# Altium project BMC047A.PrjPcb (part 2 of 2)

## Sheet BMC047A USB.SchDoc
size 431 x 279 mm; Date: Not shown in title block; ApprovedBy: Not shown in title block; CheckedBy: Not shown in title block; Author: Not shown in title block; CompanyName: Not shown in title block; Engineer: Not shown in title block; Organization: Not shown in title block; Address1: Not shown in title block; Address2: Not shown in title block; Address3: Not shown in title block; Address4: Not shown in title block; DocumentNumber: 2; Revision: Use project parameter SCH_Rev; SheetNumber: 2; SheetTotal: 3; PageSetup: Record=PageOptions¦CenterHorizontal=True¦CenterVertical=True¦PrintScale=0.96¦XCorrection=1.00¦YCorrection=1.00¦PrintKind=0¦BorderSize=5000000¦LeftOffset=0¦BottomOffset=0¦Orientation=2¦PaperLength=1000¦PaperWidth=1000¦Scale=100¦PaperSource=15¦PrintQuality=-3¦MediaType=1¦DitherType=10¦PrintScaleMode=1¦PaperKind=Tabloid (11 x 17")¦PaperIndex=17

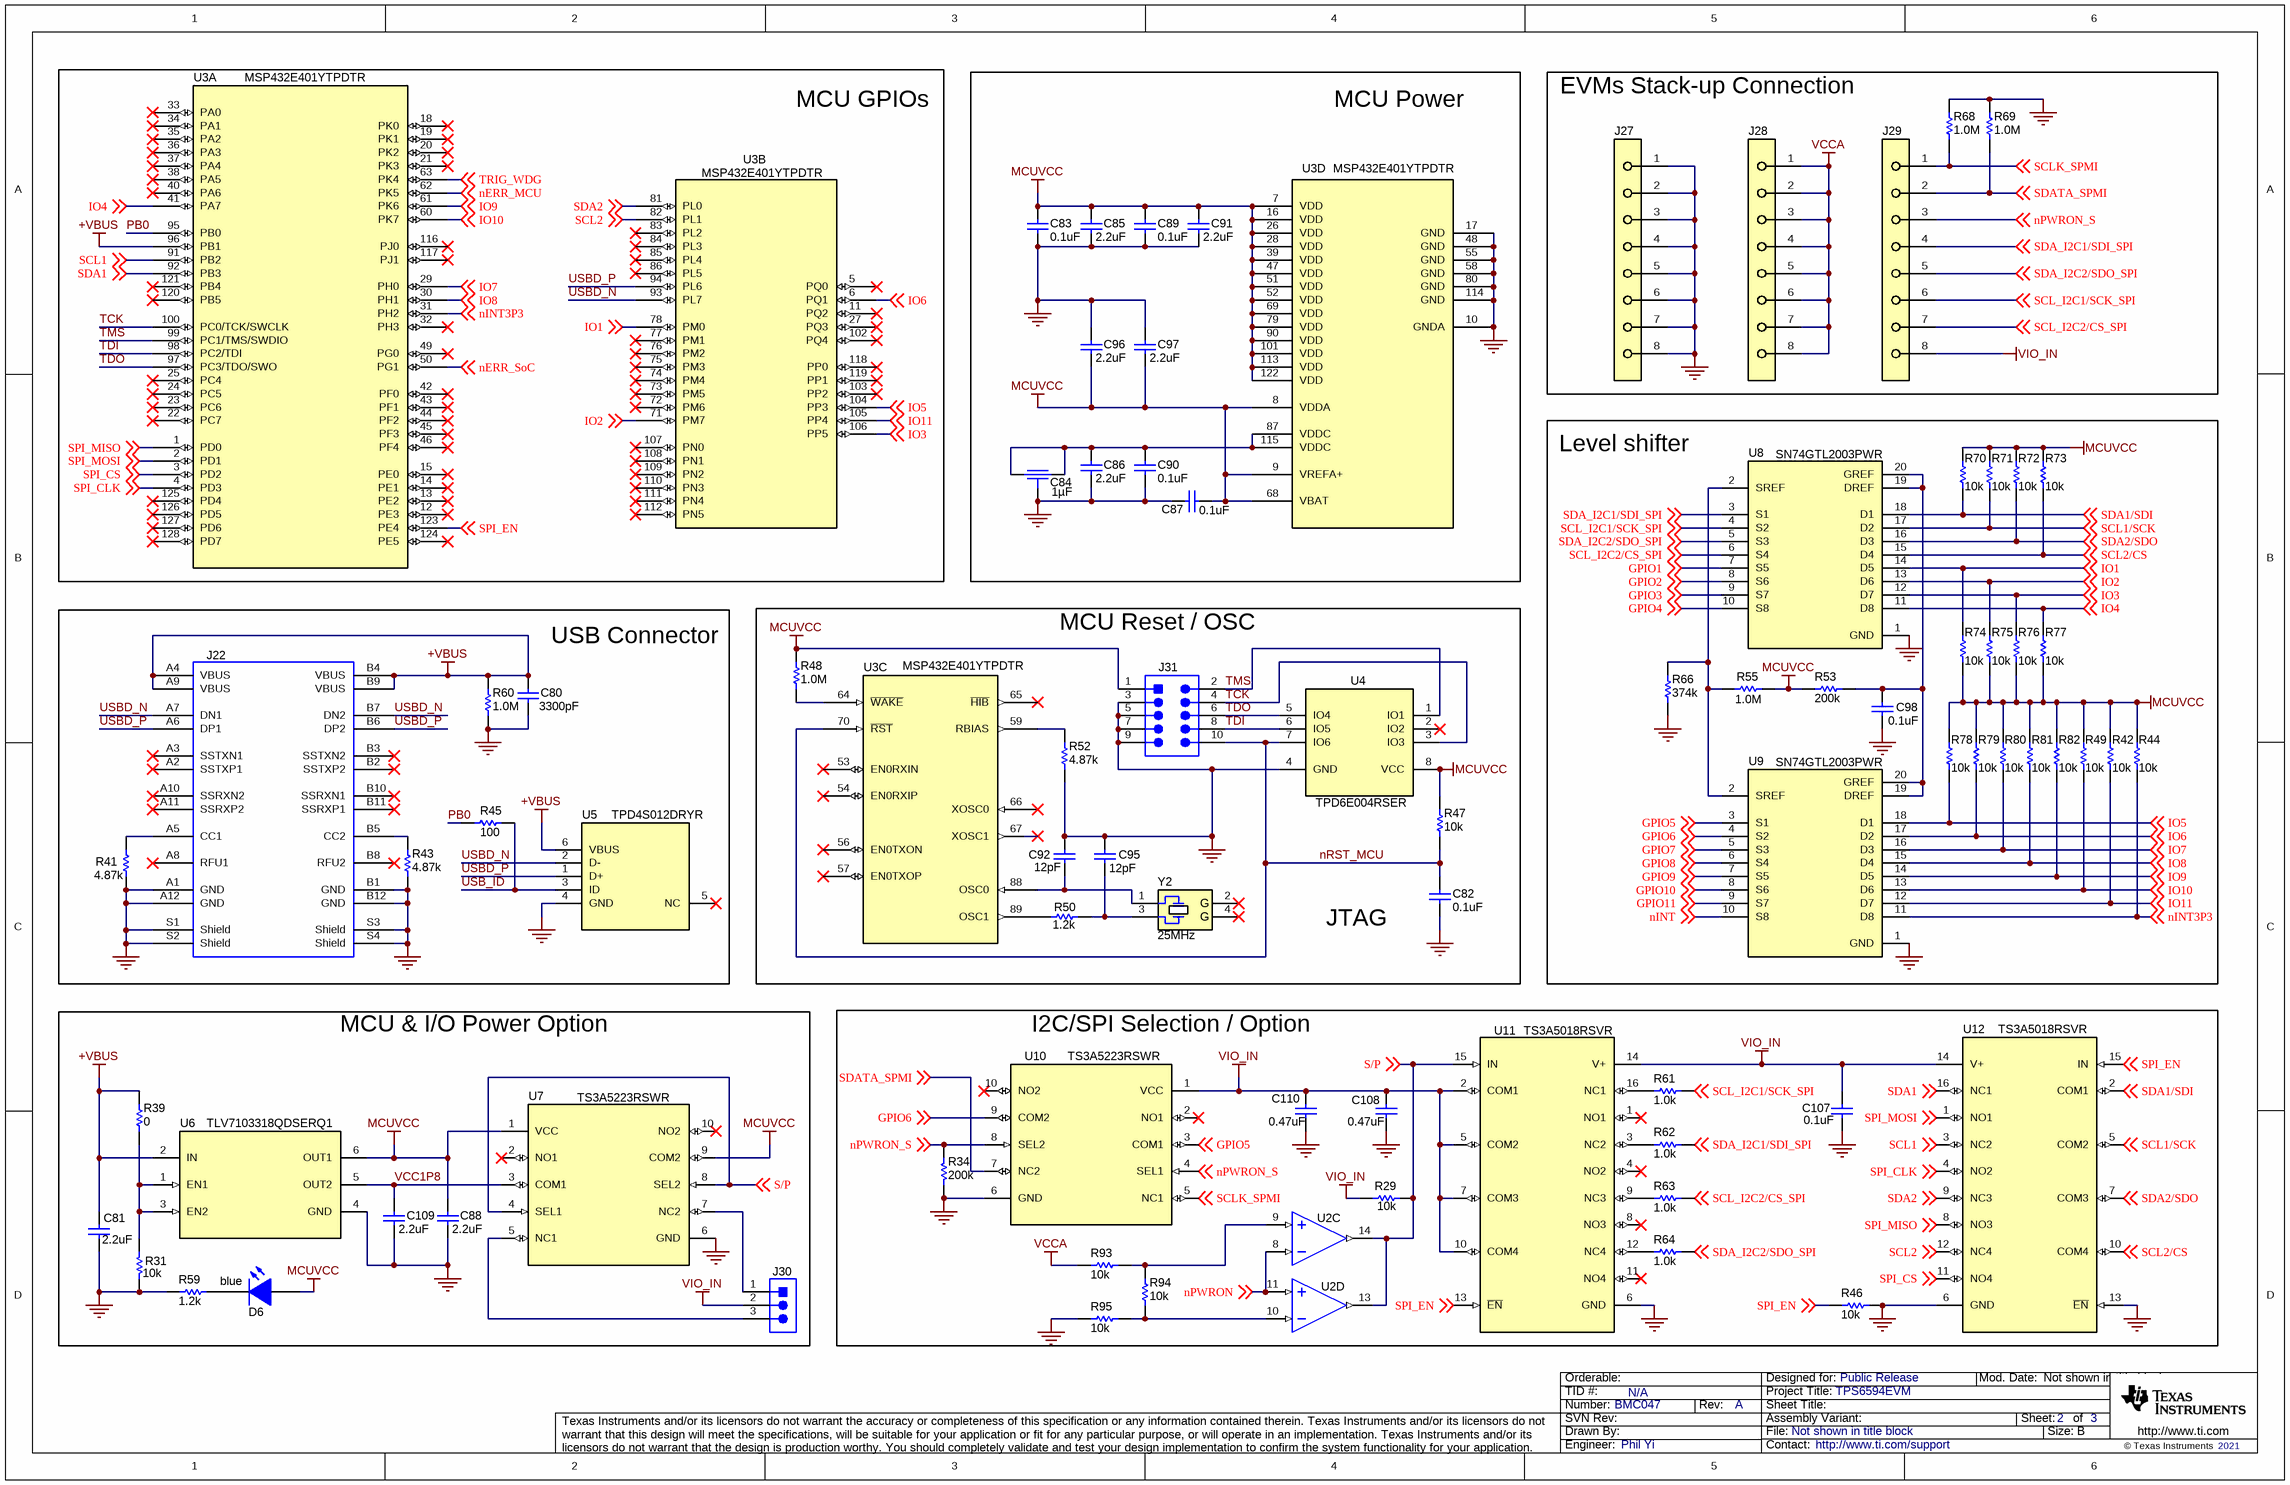
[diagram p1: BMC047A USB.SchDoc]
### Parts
C80  ValueDisplayed: 3300pF  [0603L]  (hidden comment: C0603C332K5RACTU)
C81  ValueDisplayed: 2.2uF  [0603L]  (hidden comment: CGA3E1X7S1C225M080AC)
C82  ValueDisplayed: 0.1uF  [0402L]  (hidden comment: GCM155R71C104KA55D)
C83  ValueDisplayed: 0.1uF  [0402L]  (hidden comment: GCM155R71C104KA55D)
C84  ValueDisplayed: 1µF  [FP-NFM15HC105D0G3_0402-MFG]  (hidden comment: NFM15HC105D0G3)
C85  ValueDisplayed: 2.2uF  [0603L]  (hidden comment: CGA3E1X7S1C225M080AC)
C86  ValueDisplayed: 2.2uF  [0603L]  (hidden comment: CGA3E1X7S1C225M080AC)
C87  ValueDisplayed: 0.1uF  [0402L]  (hidden comment: GCM155R71C104KA55D)
C88  ValueDisplayed: 2.2uF  [0603L]  (hidden comment: CGA3E1X7S1C225M080AC)
C89  ValueDisplayed: 0.1uF  [0402L]  (hidden comment: GCM155R71C104KA55D)
C90  ValueDisplayed: 0.1uF  [0402L]  (hidden comment: GCM155R71C104KA55D)
C91  ValueDisplayed: 2.2uF  [0603L]  (hidden comment: CGA3E1X7S1C225M080AC)
C92  ValueDisplayed: 12pF  [0402L]  (hidden comment: GCM1555C1H120JA16J)
C95  ValueDisplayed: 12pF  [0402L]  (hidden comment: GCM1555C1H120JA16J)
C96  ValueDisplayed: 2.2uF  [0603L]  (hidden comment: CGA3E1X7S1C225M080AC)
C97  ValueDisplayed: 2.2uF  [0603L]  (hidden comment: CGA3E1X7S1C225M080AC)
C98  value 0.1uF  [0402L]  (hidden comment: GCM155R71C104KA55D)
C107  ValueDisplayed: 0.1uF  [0402L]  (hidden comment: GCM155R71C104KA55D)
C108  ValueDisplayed: 0.47uF  [0402L]  (hidden comment: GCM155C71A474KE36D)
C109  ValueDisplayed: 2.2uF  [0603L]  (hidden comment: CGA3E1X7S1C225M080AC)
C110  ValueDisplayed: 0.47uF  [0402L]  (hidden comment: GCM155C71A474KE36D)
D6  Color: blue  [LB Q39G_BLUE]  (hidden comment: LB Q39G-L2N2-35-1)
J22  12401610E4#2A  [Amphenol_12401610E4_2A]  (value not drawn)
J27  ESQ-108-14-T-S  [FP-ESQ-108-14-T-S_HDR8-MFG]  (value not drawn)
J28  ESQ-108-14-T-S  [FP-ESQ-108-14-T-S_HDR8-MFG]  (value not drawn)
J29  ESQ-108-14-T-S  [FP-ESQ-108-14-T-S_HDR8-MFG]  (value not drawn)
J30  61300311121  [WURTH_61300311121]  (value not drawn)
J31  SH-105-01-F-DV-K  [Samtec_FTSH-105-01-x-DV-K]  (value not drawn)
R29  ValueDisplayed: 10k  [0402L]  (hidden comment: CRCW040210K0JNED)
R31  ValueDisplayed: 10k  [0402L]  (hidden comment: CRCW040210K0JNED)
R34  ValueDisplayed: 200k  [0402]  (hidden comment: CRCW0402200KJNED)
R39  ValueDisplayed: 0  [0402L]  (hidden comment: RK73Z1ETTP)
R41  ValueDisplayed: 4.87k  [0402L]  (hidden comment: CRCW04024K87FKED)
R42  ValueDisplayed: 10k  [0402L]  (hidden comment: CRCW040210K0JNED)
R43  ValueDisplayed: 4.87k  [0402L]  (hidden comment: CRCW04024K87FKED)
R44  ValueDisplayed: 10k  [0402L]  (hidden comment: CRCW040210K0JNED)
R45  ValueDisplayed: 100  [0402L]  (hidden comment: CRCW0402100RJNED)
R46  ValueDisplayed: 10k  [0402L]  (hidden comment: CRCW040210K0JNED)
R47  ValueDisplayed: 10k  [0402L]  (hidden comment: CRCW040210K0JNED)
R48  ValueDisplayed: 1.0M  [0402L]  (hidden comment: CRCW04021M00JNED)
R49  ValueDisplayed: 10k  [0402L]  (hidden comment: CRCW040210K0JNED)
R50  ValueDisplayed: 1.2k  [0402L]  (hidden comment: CRCW04021K20JNED)
R52  ValueDisplayed: 4.87k  [0402L]  (hidden comment: CRCW04024K87FKED)
R53  ValueDisplayed: 200k  [0402]  (hidden comment: CRCW0402200KJNED)
R55  ValueDisplayed: 1.0M  [0402L]  (hidden comment: CRCW04021M00JNED)
R59  ValueDisplayed: 1.2k  [0402L]  (hidden comment: CRCW04021K20JNED)
R60  ValueDisplayed: 1.0M  [0402L]  (hidden comment: CRCW04021M00JNED)
R61  value 1.0k  [0402L]  (hidden comment: CRCW04021K00JNED)
R62  value 1.0k  [0402L]  (hidden comment: CRCW04021K00JNED)
R63  value 1.0k  [0402L]  (hidden comment: CRCW04021K00JNED)
R64  value 1.0k  [0402L]  (hidden comment: CRCW04021K00JNED)
R66  ValueDisplayed: 374k  [0402L]  (hidden comment: CRCW0402374KFKED)
R68  ValueDisplayed: 1.0M  [0402L]  (hidden comment: CRCW04021M00JNED)
R69  ValueDisplayed: 1.0M  [0402L]  (hidden comment: CRCW04021M00JNED)
R70  ValueDisplayed: 10k  [0402L]  (hidden comment: CRCW040210K0JNED)
R71  ValueDisplayed: 10k  [0402L]  (hidden comment: CRCW040210K0JNED)
R72  ValueDisplayed: 10k  [0402L]  (hidden comment: CRCW040210K0JNED)
R73  ValueDisplayed: 10k  [0402L]  (hidden comment: CRCW040210K0JNED)
R74  ValueDisplayed: 10k  [0402L]  (hidden comment: CRCW040210K0JNED)
R75  ValueDisplayed: 10k  [0402L]  (hidden comment: CRCW040210K0JNED)
R76  ValueDisplayed: 10k  [0402L]  (hidden comment: CRCW040210K0JNED)
R77  ValueDisplayed: 10k  [0402L]  (hidden comment: CRCW040210K0JNED)
R78  ValueDisplayed: 10k  [0402L]  (hidden comment: CRCW040210K0JNED)
R79  ValueDisplayed: 10k  [0402L]  (hidden comment: CRCW040210K0JNED)
R80  ValueDisplayed: 10k  [0402L]  (hidden comment: CRCW040210K0JNED)
R81  ValueDisplayed: 10k  [0402L]  (hidden comment: CRCW040210K0JNED)
R82  ValueDisplayed: 10k  [0402L]  (hidden comment: CRCW040210K0JNED)
R93  ValueDisplayed: 10k  [0402L]  (hidden comment: CRCW040210K0JNED)
R94  ValueDisplayed: 10k  [0402L]  (hidden comment: CRCW040210K0JNED)
R95  ValueDisplayed: 10k  [0402L]  (hidden comment: CRCW040210K0JNED)
U2  LM2901AVQPWRQ1  [PW0014A_N]  (value not drawn)  (parts C,D of 5)
U3  MSP432E401YTPDTR  [PDT0128A]  (parts A,B,C,D of 4)
U4  TPD6E004RSER  [RSE0008A]
U5  TPD4S012DRYR  [DRY0006A]
U6  TLV7103318QDSERQ1  [DSE0006A]
U7  TS3A5223RSWR  [RSW0010A]
U8  SN74GTL2003PWR  [PW0020A_N]
U9  SN74GTL2003PWR  [PW0020A_N]
U10  TS3A5223RSWR  [RSW0010A]
U11  TS3A5018RSVR  [RSV0016A]
U12  TS3A5018RSVR  [RSV0016A]
Y2  Frequency_Fixed: 25MHz  [NDK_NX3225GA]  (hidden comment: NX3225GA-25.000M-STD-CRG-2)

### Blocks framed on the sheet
MCU GPIOs: U3
MCU Power: C83-C87 C89-C91 C96 C97 U3
EVMs Stack-up Connection: J27-J29 R68 R69
Level shifter: C98 R42 R44 R49 R53 R55 R66 R70-R82 U8 U9
USB Connector: C80 J22 R41 R43 R45 R60 U5
MCU & I/O Power Option: C81 C88 C109 D6 J30 R31 R39 R59 U6 U7
I2C/SPI Selection / Option: C107 C108 C110 R29 R34 R46 R61-R64 R93-R95 U2 U10-U12

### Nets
+VBUS: C80.1 C81.1 J22.A4(VBUS) J22.A9(VBUS) J22.B4(VBUS) J22.B9(VBUS) R39.1 R60.1 U3.96(PB1) U5.6(VBUS) U6.2(IN)
GND: C80.2 C81.2 C82.2 C83.2 C84.2 C85.2 C86.2 C87.1 C88.2 C89.2 C90.2 C91.2 C92.2 C95.2 C96.1 C97.1 C98.2 C107.1 C108.1 C109.2 C110.1 J22.A1(GND) J22.A12(GND) J22.B1(GND) J22.B12(GND) J22.S1(Shield) J22.S2(Shield) J22.S3(Shield) J22.S4(Shield) J27.1 J27.2 J27.3 J27.4 J27.5 J27.6 J27.7 J27.8 J31.3 J31.5 J31.7 J31.9 R31.1 R34.1 R41.2 R43.2 R46.1 R52.2 R59.2 R60.2 R66.1 R68.1 R69.1 R95.2 U3.10(GNDA) U3.17(GND) U3.48(GND) U3.55(GND) U3.58(GND) U3.80(GND) U3.114(GND) U4.4(GND) U5.4(GND) U6.4(GND) U7.6(GND) U8.1(GND) U9.1(GND) U10.6(GND) U11.6(GND) U12.6(GND) U12.13(~{EN})
MCUVCC: C83.1 C85.1 C87.2 C88.1 C89.1 C91.1 C96.2 C97.2 D6.1(A) J31.1 R42.1 R44.1 R47.2 R48.2 R49.1 R53.1 R55.2 R70.1 R71.1 R72.1 R73.1 R74.2 R75.2 R76.2 R77.2 R78.1 R79.1 R80.1 R81.1 R82.1 U3.7(VDD) U3.8(VDDA) U3.9(VREFA+) U3.16(VDD) U3.26(VDD) U3.28(VDD) U3.39(VDD) U3.47(VDD) U3.51(VDD) U3.52(VDD) U3.68(VBAT) U3.69(VDD) U3.79(VDD) U3.90(VDD) U3.101(VDD) U3.113(VDD) U3.122(VDD) U4.8(VCC) U6.6(OUT1) U7.1(VCC) U7.9(COM2)
VCCA: J28.1 J28.2 J28.3 J28.4 J28.5 J28.6 J28.7 J28.8 R93.1
VIO_IN: C107.2 C108.2 C110.2 J29.8 J30.2 R29.1 U10.1(VCC) U11.2(COM1) U11.5(COM2) U11.7(COM3) U11.10(COM4) U11.14(V+) U12.14(V+)
GPIO1: U8.7(S5) ; off-sheet GPIO1
GPIO2: U8.8(S6) ; off-sheet GPIO2
GPIO3: U8.9(S7) ; off-sheet GPIO3
GPIO4: U8.10(S8) ; off-sheet GPIO4
GPIO5: U9.3(S1) U10.3(COM1) ; off-sheet GPIO5
GPIO6: U9.4(S2) U10.9(COM2) ; off-sheet GPIO6
GPIO7: U9.5(S3) ; off-sheet GPIO7
GPIO8: U9.6(S4) ; off-sheet GPIO8
GPIO9: U9.7(S5) ; off-sheet GPIO9
GPIO10: U9.8(S6) ; off-sheet GPIO10
GPIO11: U9.9(S7) ; off-sheet GPIO11
IO1: R74.1 U3.78(PM0) U8.14(D5) ; off-sheet IO1
IO2: R75.1 U3.71(PM7) U8.13(D6) ; off-sheet IO2
IO3: R76.1 U3.106(PP5) U8.12(D7) ; off-sheet IO3
IO4: R77.1 U3.41(PA7) U8.11(D8) ; off-sheet IO4
IO5: R78.2 U3.104(PP3) U9.18(D1) ; off-sheet IO5
IO6: R79.2 U3.6(PQ1) U9.17(D2) ; off-sheet IO6
IO7: R80.2 U3.29(PH0) U9.16(D3) ; off-sheet IO7
IO8: R81.2 U3.30(PH1) U9.15(D4) ; off-sheet IO8
IO9: R82.2 U3.61(PK6) U9.14(D5) ; off-sheet IO9
IO10: R49.2 U3.60(PK7) U9.13(D6) ; off-sheet IO10
IO11: R42.2 U3.105(PP4) U9.12(D7) ; off-sheet IO11
nERR_MCU: U3.62(PK5) ; off-sheet nERR_MCU
nERR_SoC: U3.50(PG1) ; off-sheet nERR_SoC
nINT: U9.10(S8) ; off-sheet nINT
nINT3P3: R44.2 U3.31(PH2) U9.11(D8) ; off-sheet nINT3P3
nPWRON: U2.8(-IN3) U2.11(+IN4) ; off-sheet nPWRON
nPWRON_S: J29.3 R34.2 U10.4(SEL1) U10.8(SEL2) ; off-sheet nPWRON_S
nRST_MCU: C82.1 J31.10 R47.1 U3.70(~{RST}) U4.7(IO6)
PB0: R45.1 U3.95(PB0)
S/P: R29.2 U2.13(OUT4) U2.14(OUT3) U7.4(SEL1) U7.8(SEL2) U11.15(IN) ; off-sheet S/P
SCL1: U3.91(PB2) U12.3(NC2) ; off-sheet SCL1
SCL1/SCK: R71.2 U8.17(D2) U12.5(COM2) ; off-sheet SCL1/SCK
SCL2: U3.82(PL1) U12.12(NC4) ; off-sheet SCL2
SCL2/CS: R73.2 U8.15(D4) U12.10(COM4) ; off-sheet SCL2/CS
SCL_I2C1/SCK_SPI: J29.6 R61.2 U8.4(S2) ; off-sheet SCL_I2C1/SCK_SPI
SCL_I2C2/CS_SPI: J29.7 R63.2 U8.6(S4) ; off-sheet SCL_I2C2/CS_SPI
SCLK_SPMI: J29.1 R68.2 U10.5(NC1) ; off-sheet SCLK_SPMI
SDA1: U3.92(PB3) U12.16(NC1) ; off-sheet SDA1
SDA1/SDI: R70.2 U8.18(D1) U12.2(COM1) ; off-sheet SDA1/SDI
SDA2: U3.81(PL0) U12.9(NC3) ; off-sheet SDA2
SDA2/SDO: R72.2 U8.16(D3) U12.7(COM3) ; off-sheet SDA2/SDO
SDA_I2C1/SDI_SPI: J29.4 R62.2 U8.3(S1) ; off-sheet SDA_I2C1/SDI_SPI
SDA_I2C2/SDO_SPI: J29.5 R64.2 U8.5(S3) ; off-sheet SDA_I2C2/SDO_SPI
SDATA_SPMI: J29.2 R69.2 U10.7(NC2) ; off-sheet SDATA_SPMI
SPI_CLK: U3.4(PD3) U12.4(NO2) ; off-sheet SPI_CLK
SPI_CS: U3.3(PD2) U12.11(NO4) ; off-sheet SPI_CS
SPI_EN: R46.2 U3.123(PE4) U11.13(~{EN}) U12.15(IN) ; off-sheet SPI_EN
SPI_MISO: U3.1(PD0) U12.8(NO3) ; off-sheet SPI_MISO
SPI_MOSI: U3.2(PD1) U12.1(NO1) ; off-sheet SPI_MOSI
TCK: J31.4 U3.100(PC0/TCK/SWCLK) U4.3(IO3)
TDI: J31.8 U3.98(PC2/TDI) U4.6(IO5)
TDO: J31.6 U3.97(PC3/TDO/SWO) U4.5(IO4)
TMS: J31.2 U3.99(PC1/TMS/SWDIO) U4.1(IO1)
TRIG_WDG: U3.63(PK4) ; off-sheet TRIG_WDG
USB_ID: R45.2 U5.3(ID)
USBD_N: J22.A7(DN1) J22.B7(DN2) U3.93(PL7) U5.2(D-)
USBD_P: J22.A6(DP1) J22.B6(DP2) U3.94(PL6) U5.1(D+)
VCC1P8: C109.1 U6.5(OUT2) U7.3(COM1)
NetC84_1: C84.1 C84.3 C86.1 C90.1 U3.87(VDDC) U3.115(VDDC)
NetC92_1: C92.1 U3.88(OSC0) Y2.1
NetC95_1: C95.1 R50.2 Y2.3
NetC98_1: C98.1 R53.2 U8.19(DREF) U8.20(GREF) U9.19(DREF) U9.20(GREF)
NetD6_2: D6.2(K) R59.1
NetJ22_A5: J22.A5(CC1) R41.1
NetJ22_B5: J22.B5(CC2) R43.1
NetJ30_1: J30.1 U7.7(NC2)
NetJ30_3: J30.3 U7.5(NC1)
NetR31_2: R31.2 R39.2 U6.1(EN1) U6.3(EN2)
NetR48_1: R48.1 U3.64(~{WAKE})
NetR50_1: R50.1 U3.89(OSC1)
NetR52_1: R52.1 U3.59(RBIAS)
NetR55_1: R55.1 R66.2 U8.2(SREF) U9.2(SREF)
NetR61_1: R61.1 U11.16(NC1)
NetR62_1: R62.1 U11.3(NC2)
NetR63_1: R63.1 U11.9(NC3)
NetR64_1: R64.1 U11.12(NC4)
NetR93_2: R93.2 R94.2 U2.9(+IN3)
NetR94_1: R94.1 R95.1 U2.10(-IN4)

Not connected (* = marked no-connect by the designer): J22 A2(SSTXP1)* A3(SSTXN1)* A8(RFU1)* A10(SSRXN2)* A11(SSRXP2)* B2(SSTXP2)* B3(SSTXN2)* B8(RFU2)* B10(SSRXN1)* B11(SSRXP1)*; U3 5(PQ0)* 11(PQ2)* 12(PE3)* 13(PE2)* 14(PE1)* 15(PE0)* 18(PK0)* 19(PK1)* 20(PK2)* 21(PK3)* 22(PC7)* 23(PC6)* 24(PC5)* 25(PC4)* 27(PQ3)* 32(PH3)* 33(PA0)* 34(PA1)* 35(PA2)* 36(PA3)* 37(PA4)* 38(PA5)* 40(PA6)* 42(PF0)* 43(PF1)* 44(PF2)* 45(PF3)* 46(PF4)* 49(PG0)* 53(EN0RXIN)* 54(EN0RXIP)* 56(EN0TXON)* 57(EN0TXOP)* 65(~{HIB})* 66(XOSC0)* 67(XOSC1)* 72(PM6)* 73(PM5)* 74(PM4)* 75(PM3)* 76(PM2)* 77(PM1)* 83(PL2)* 84(PL3)* 85(PL4)* 86(PL5)* 102(PQ4)* 103(PP2)* 107(PN0)* 108(PN1)* 109(PN2)* 110(PN3)* 111(PN4)* 112(PN5)* 116(PJ0)* 117(PJ1)* 118(PP0)* 119(PP1)* 120(PB5)* 121(PB4)* 124(PE5)* 125(PD4)* 126(PD5)* 127(PD6)* 128(PD7)*; U4 2(IO2)*; U5 5(NC)*; U7 2(NO1)* 10(NO2)*; U10 2(NO1)* 10(NO2)*; U11 1(NO1)* 4(NO2)* 8(NO3)* 11(NO4)*; Y2 2(GND)* 4(GND)*

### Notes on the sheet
- MCU Reset / OSC
- JTAG

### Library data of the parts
C80 = CMP-0006922-4: CAP, CERM, 3300 pF, 50 V, +/- 10%, X7R, 0603; Manufacturer: Kemet; TaMin_C: -55°C; Polarized: N; SizeAreaWB_mm2: 4.68; Value1: Unknown; U/M: EA; Value: 3300pF; TaMax_C: 125°C; SizeZ_mm: 1; SizeX_mm: 1.6; SizeY_mm: 0.8; Cap_Case: 0603; Value2: 50V; SizeArea_mm2: 1.28; Cap_F: 3.3nF; AEC Category: Q200
C81 = CMP-0007068-4: CAP, CERM, 2.2 uF, 16 V, +/- 20%, X7S, AEC-Q200 Grade 1, 0603; Manufacturer: TDK; SizeAreaWB_mm2: 4.68; Cap_F: 2.2µF; Value1: Unknown; Value2: 16V; Value: 2.2uF; AEC Grade: 1; SizeX_mm: 1.6; TaMin_C: -55°C; AEC Category: Q200; U/M: EA; TaMax_C: 125°C; SizeArea_mm2: 1.28; Polarized: N; SizeY_mm: 0.8; Cap_Case: 0603; AEC Qualified: Y
C82 C83 C87 C89 C90 C107 = CMP-0006351-2: CAP, CERM, 0.1 uF, 16 V, +/- 10%, X7R, 0402; Manufacturer: MuRata; TaMin_C: -55°C; Polarized: N; SizeAreaWB_mm2: 3; Value1: Unknown; U/M: EA; Value: 0.1uF; TaMax_C: 125°C; SizeZ_mm: 0.6; SizeX_mm: 1; SizeY_mm: 0.5; Cap_Case: 0402; Value2: 16V; Cap_F: 100nF; AEC Category: Q200
C84 = CMP-0086486-3: 3 Terminals Chip Multilayer Ceramic Capacitor (EMIFIL); Manufacturer: Murata; Tolerance_%: 20%; SizeZ_mm: 0.5mm; AEC Qualified: No; VDC_V: 4V
C85 C86 C88 C91 C96 C97 C109 = CMP-0007068-4: CAP, CERM, 2.2 uF, 16 V, +/- 20%, X7S, AEC-Q200 Grade 1, 0603; Manufacturer: TDK; TaMin_C: -55°C; Polarized: N; SizeAreaWB_mm2: 4.68; Value1: Unknown; U/M: EA; Value: 2.2uF; TaMax_C: 125°C; SizeZ_mm: 1; SizeX_mm: 1.6; SizeY_mm: 0.8; Cap_Case: 0603; Value2: 16V; SizeArea_mm2: 1.28; AEC Qualified: Y; Cap_F: 2.2µF; AEC Category: Q200
C92 C95 = CMP-0085816-1: CAP, CERM, 12 pF, 50 V,+/- 5%, C0G/NP0, AEC-Q200 Grade 1, 0402; Manufacturer: MuRata; TaMin_C: -55°C; Polarized: N; SizeAreaWB_mm2: 3; U/M: EA; Value: 12pF; TaMax_C: 125°C; SizeZ_mm: 0.6; SizeX_mm: 1; SizeY_mm: 0.5; Cap_Case: 0402; Value2: 50V; AEC Qualified: Y; AEC Category: Q200
C98 = CMP-0006351-2: CAP, CERM, 0.1 uF, 16 V, +/- 10%, X7R, 0402; Manufacturer: MuRata; TaMin_C: -55°C; Polarized: N; SizeAreaWB_mm2: 3; Value1: Unknown; U/M: EA; TaMax_C: 125°C; SizeZ_mm: 0.6; SizeX_mm: 1; SizeY_mm: 0.5; Cap_Case: 0402; Value2: 16V; Cap_F: 100nF; AEC Category: Q200
C108 C110 = CMP-0064967-2: CAP, CERM, 0.47 uF, 10 V,+/- 10%, X7S, 0402; Manufacturer: MuRata; TaMin_C: -55°C; Polarized: N; SizeAreaWB_mm2: 3; Value1: Unknown; U/M: EA; Value: 0.47uF; TaMax_C: 125°C; SizeZ_mm: 0.6; SizeX_mm: 1; SizeY_mm: 0.5; Cap_Case: 0402; Value2: 10V; Cap_F: 470nF; AEC Category: Q200
D6 = CMP-0002849-2: LED, Blue, SMD; Manufacturer: OSRAM; Tjmax_C: 95°C; Value1: W; Io_A: 150mA; Vf_V: 2.85V
J22 = CMP-0075218-1: Receptacle, 0.5mm, USB TYPE C, R/A, SMT; Manufacturer: Amphenol Canada; CNHeader: False; Current_A: 5A; Green_Lifecycle: Not Set; Gender: Female; Green_REACh: Incomplete; Row_Count: 2; Pitch_mm: 0.5; ContactFinish: Tin; CT: True; Cert_UL: Y
J27-J29 = CMP-0087040-2: Board-To-Board Connector, Vertical, ESQ Series, 8 Contacts, Receptacle, 2.54 mm, Through Hole; Manufacturer: Samtec; Voltage_V: 550V; Current_A: 5.7A; ContactFinish: Tin,Nickel; Row_Count: 1
J30 = CMP-0054796-2: Header, 2.54 mm, 3x1, Gold, TH; Manufacturer: Wurth Elektronik; Pitch_mm: 2.54; Green_Lifecycle: Active; Cert_UL: Y; Shrouded: N; Green_REACh: Passed; Gender: Male; Row_Count: 1
J31 = CMP-0075670-2: Header (Shrouded), 1.27mm, 5x2, Gold, SMT; PartNumber: FTSH-105-01-F-DV-K; Manufacturer: Samtec; Pitch_mm: 1.27; Gender: Male; Cert_CSA: Y; Current_A: 3.3A; Row_Count: 2
R29 R31 R42 R44 R46 R47 R49 R70-R82 R93-R95 = CMP-0026825-5: RES, 10 k, 5%, 0.063 W, AEC-Q200 Grade 0, 0402; Manufacturer: Vishay-Dale; Power_W: 63mW; TempCo: 200 ppm/C; Value_Code: 10k0; Value: 10k; EIA_Code: E24; SizeX_mm: 1; SizeY_mm: 0.5; SizeZ_mm: 0.6; Value2: 0.063W; AEC Qualified: Y; VDC_V: 50V; AEC Category: Q200; AEC Grade: 0
R34 R53 = CMP-0026873-2: RES, 200 k, 5%, 0.063 W, AEC-Q200 Grade 0, 0402; Manufacturer: Vishay-Dale; Power_W: 63mW; TempCo: 200 ppm/C; Value: 200k; EIA_Code: E24; SizeX_mm: 1; SizeY_mm: 0.5; SizeZ_mm: 0.6; Value2: 0.063W; AEC Qualified: Y; VDC_V: 50V; AEC Category: Q200; AEC Grade: 0
R39 = CMP-0027007-2: RES, 0, 5%, 0.063 W, AEC-Q200 Grade 0, 0402; Manufacturer: KOA Speer; Power_W: 63mW; TempCo: ppm/C; Value_Code: 0000; U/M: EA; Value: 0; EIA_Code: E24; SizeX_mm: 1; SizeY_mm: 0.5; SizeZ_mm: 0.6; Value2: 0.063W; AEC Qualified: Y; AEC Category: Q200
R41 R43 R52 = CMP-0026413-2: RES, 4.87 k, 1%, 0.063 W, AEC-Q200 Grade 0, 0402; Manufacturer: Vishay-Dale; Power_W: 63mW; TempCo: 100 ppm/C; Value_Code: 4k87; Value: 4.87k; EIA_Code: E96; SizeX_mm: 1; SizeY_mm: 0.5; SizeZ_mm: 0.6; Value2: 0.063W; AEC Qualified: Y; VDC_V: 50V; AEC Category: Q200; AEC Grade: 0
R45 = CMP-0026824-3: RES, 100, 5%, 0.063 W, AEC-Q200 Grade 0, 0402; Manufacturer: Vishay-Dale; Power_W: 63mW; TempCo: 200 ppm/C; Value_Code: 100R; Value: 100; EIA_Code: E24; SizeX_mm: 1; SizeY_mm: 0.5; SizeZ_mm: 0.6; Value2: 0.063W; AEC Qualified: Y; VDC_V: 50V; AEC Category: Q200; AEC Grade: 0
R48 R55 R60 R68 R69 = CMP-0026859-2: RES, 1.0 M, 5%, 0.063 W, AEC-Q200 Grade 0, 0402; Manufacturer: Vishay-Dale; Power_W: 63mW; TempCo: 200 ppm/C; Value_Code: 1M00; Value: 1.0Meg; EIA_Code: E24; Res_ohm: 1M; SizeX_mm: 1; SizeY_mm: 0.5; SizeZ_mm: 0.6; Value2: 0.063W; AEC Qualified: Y; VDC_V: 50V; AEC Category: Q200; AEC Grade: 0
R50 R59 = CMP-0026854-5: RES, 1.2 k, 5%, 0.063 W, AEC-Q200 Grade 0, 0402; Manufacturer: Vishay-Dale; Power_W: 63mW; TempCo: 200 ppm/C; Value_Code: 1k20; Value: 1.2k; EIA_Code: E24; SizeX_mm: 1; SizeY_mm: 0.5; SizeZ_mm: 0.6; Value2: 0.063W; AEC Qualified: Y; VDC_V: 50V; AEC Category: Q200; AEC Grade: 0
R61-R64 = CMP-0026852-3: RES, 1.0 k, 5%, 0.063 W, AEC-Q200 Grade 0, 0402; Manufacturer: Vishay-Dale; Power_W: 63mW; TempCo: 200 ppm/C; Value_Code: 1k00; EIA_Code: E24; Res_ohm: 1k; SizeX_mm: 1; SizeY_mm: 0.5; SizeZ_mm: 0.6; Value2: 0.063W; AEC Qualified: Y; VDC_V: 50V; AEC Category: Q200; AEC Grade: 0
R66 = CMP-0026317-2: RES, 374 k, 1%, 0.063 W, AEC-Q200 Grade 0, 0402; Manufacturer: Vishay-Dale; Power_W: 63mW; TempCo: 100 ppm/C; Value: 374k; EIA_Code: E96; SizeX_mm: 1; SizeY_mm: 0.5; SizeZ_mm: 0.6; Value2: 0.063W; AEC Qualified: Y; VDC_V: 50V; AEC Category: Q200; AEC Grade: 0
U2 = CMP-0065405-2: AEC-Q100 Quad Comparator, PW0014A (TSSOP-14); Manufacturer: Texas Instruments; CompType: IC; SizeY_mm: 5.0; SizeAreaWB_mm2: 58.8; Rating: Automotive; SizeZ_mm: 1.2; AEC Category: Q200; AEC Qualified: Y; SizeArea_mm2: 32.0; SizeX_mm: 6.4
U3 = CMP-0077954-1: MSP432E401YTPDT, PDT0128A (TQFP-128); Alternate Manufacturer: Texas Instruments; SizeAreaWB_mm2: 324; SizeZ_mm: 1.2; SizeX_mm: 16; SizeArea_mm2: 256; CompType: IC; AEC Qualified: N; AEC Category: Q200
U4 = CMP-0043125-4: Low-Capacitance 6-Channel +/-15 kV ESD Protection Array for High-Speed Data Interfaces, RSE0008A (UQFN-8); Manufacturer: Texas Instruments; IO Leakage Current(nA): 1; IO Capacitance(Typ)(pF): 1.6; 1394 / Firewire: TRUE; Eco-Plan: Green (RoHS & no Sb/Br); SubFamily: ESD Solution; Breakdown Voltage(Min)(V): 6; IEC 61000-4-2 Air-Gap(+/- kV): 12; IEC 61000-4-2 Contact(+/- kV): 8; AEC Category: Q200; AEC Qualified: N; CompType: IC; SizeAreaWB_mm2: 6.25; SizeArea_mm2: 2.25; SizeX_mm: 1.5; SizeZ_mm: 0.6
U5 = CMP-0043122-3: 4-Channel USB ESD Solution with Power Clamp, DRY0006A (USON-6); Manufacturer: Texas Instruments; IO Leakage Current(nA): 10; USB High Speed: TRUE; Eco-Plan: Green (RoHS & no Sb/Br); Breakdown Voltage(Min)(V): 6; IO Capacitance(Typ)(pF): 0.8; AEC Category: Q200; AEC Qualified: N; CompType: IC; SizeAreaWB_mm2: 4.9; SizeArea_mm2: 1.45; SizeX_mm: 1.0; SizeZ_mm: 0.6; Rating: Catalog
U6 = CMP-0073729-1: Automotive Catalog, Dual, 200mA, Low-IQ Low-Dropout Regulator for Portable Devices, DSE0006A (WSON-6); Alternate Manufacturer: Texas Instruments; SizeAreaWB_mm2: 6.25; U/M: EA; SizeZ_mm: 0.8; SizeX_mm: 1.5; SizeArea_mm2: 2.25; CompType: IC
U7 U10 = CMP-0085520-1: 0.5Ω Dual SPDT Bidirectional Analog Switch, RSW0010A (UQFN-10); Manufacturer: Texas Instruments; Rating: Catalog; SizeY_mm: 1.8; AEC Qualified: N; SizeZ_mm: 0.55; CompType: IC; SizeArea_mm2: 2.52; AEC Category: Q200; SizeAreaWB_mm2: 6.72; SizeX_mm: 1.4
U8 U9 = CMP-0066429-1: 8-BIT BIDIRECTIONAL LOW-VOLTAGE TRANSLATOR, PW0020A (TSSOP-20); Alternate Manufacturer: Texas Instruments; SizeAreaWB_mm2: 73.96; U/M: EA; SizeZ_mm: 1.2; SizeX_mm: 6.6; SizeArea_mm2: 43.56; CompType: IC
U11 U12 = CMP-0067415-1: 10-Ohm Quad SPDT Analog Switch, RSV0016A (UQFN-16); Alternate Manufacturer: Texas Instruments; SizeAreaWB_mm2: 10.08; U/M: EA; SizeZ_mm: 0.55; SizeX_mm: 1.8; SizeY_mm: 2.6; SizeArea_mm2: 4.68; CompType: IC
Y2 = CMP-0004652-3: Crystal, 25 MHz, 8pF, SMD; Manufacturer: NDK; TaMax_C: 85°C; TaMin_C: -40°C; Frequency Stability: +/-30ppm

## Sheet BMC047A Hardware.SchDoc
size 431 x 279 mm; Date: Not shown in title block; ApprovedBy: Not shown in title block; CheckedBy: Not shown in title block; Author: Not shown in title block; CompanyName: Not shown in title block; Engineer: Not shown in title block; Organization: Not shown in title block; Address1: Not shown in title block; Address2: Not shown in title block; Address3: Not shown in title block; Address4: Not shown in title block; DocumentNumber: 3; Revision: Use project parameter SCH_Rev; SheetNumber: 3; SheetTotal: 3; PageSetup: Record=PageOptions¦CenterHorizontal=True¦CenterVertical=True¦PrintScale=1.00¦XCorrection=1.00¦YCorrection=1.00¦PrintKind=0¦BorderSize=5000000¦LeftOffset=0¦BottomOffset=0¦Orientation=2¦PaperLength=1000¦PaperWidth=1000¦Scale=100¦PaperSource=15¦PrintQuality=600¦MediaType=1¦DitherType=10¦PaperKind=Letter¦PrintScaleMode=1

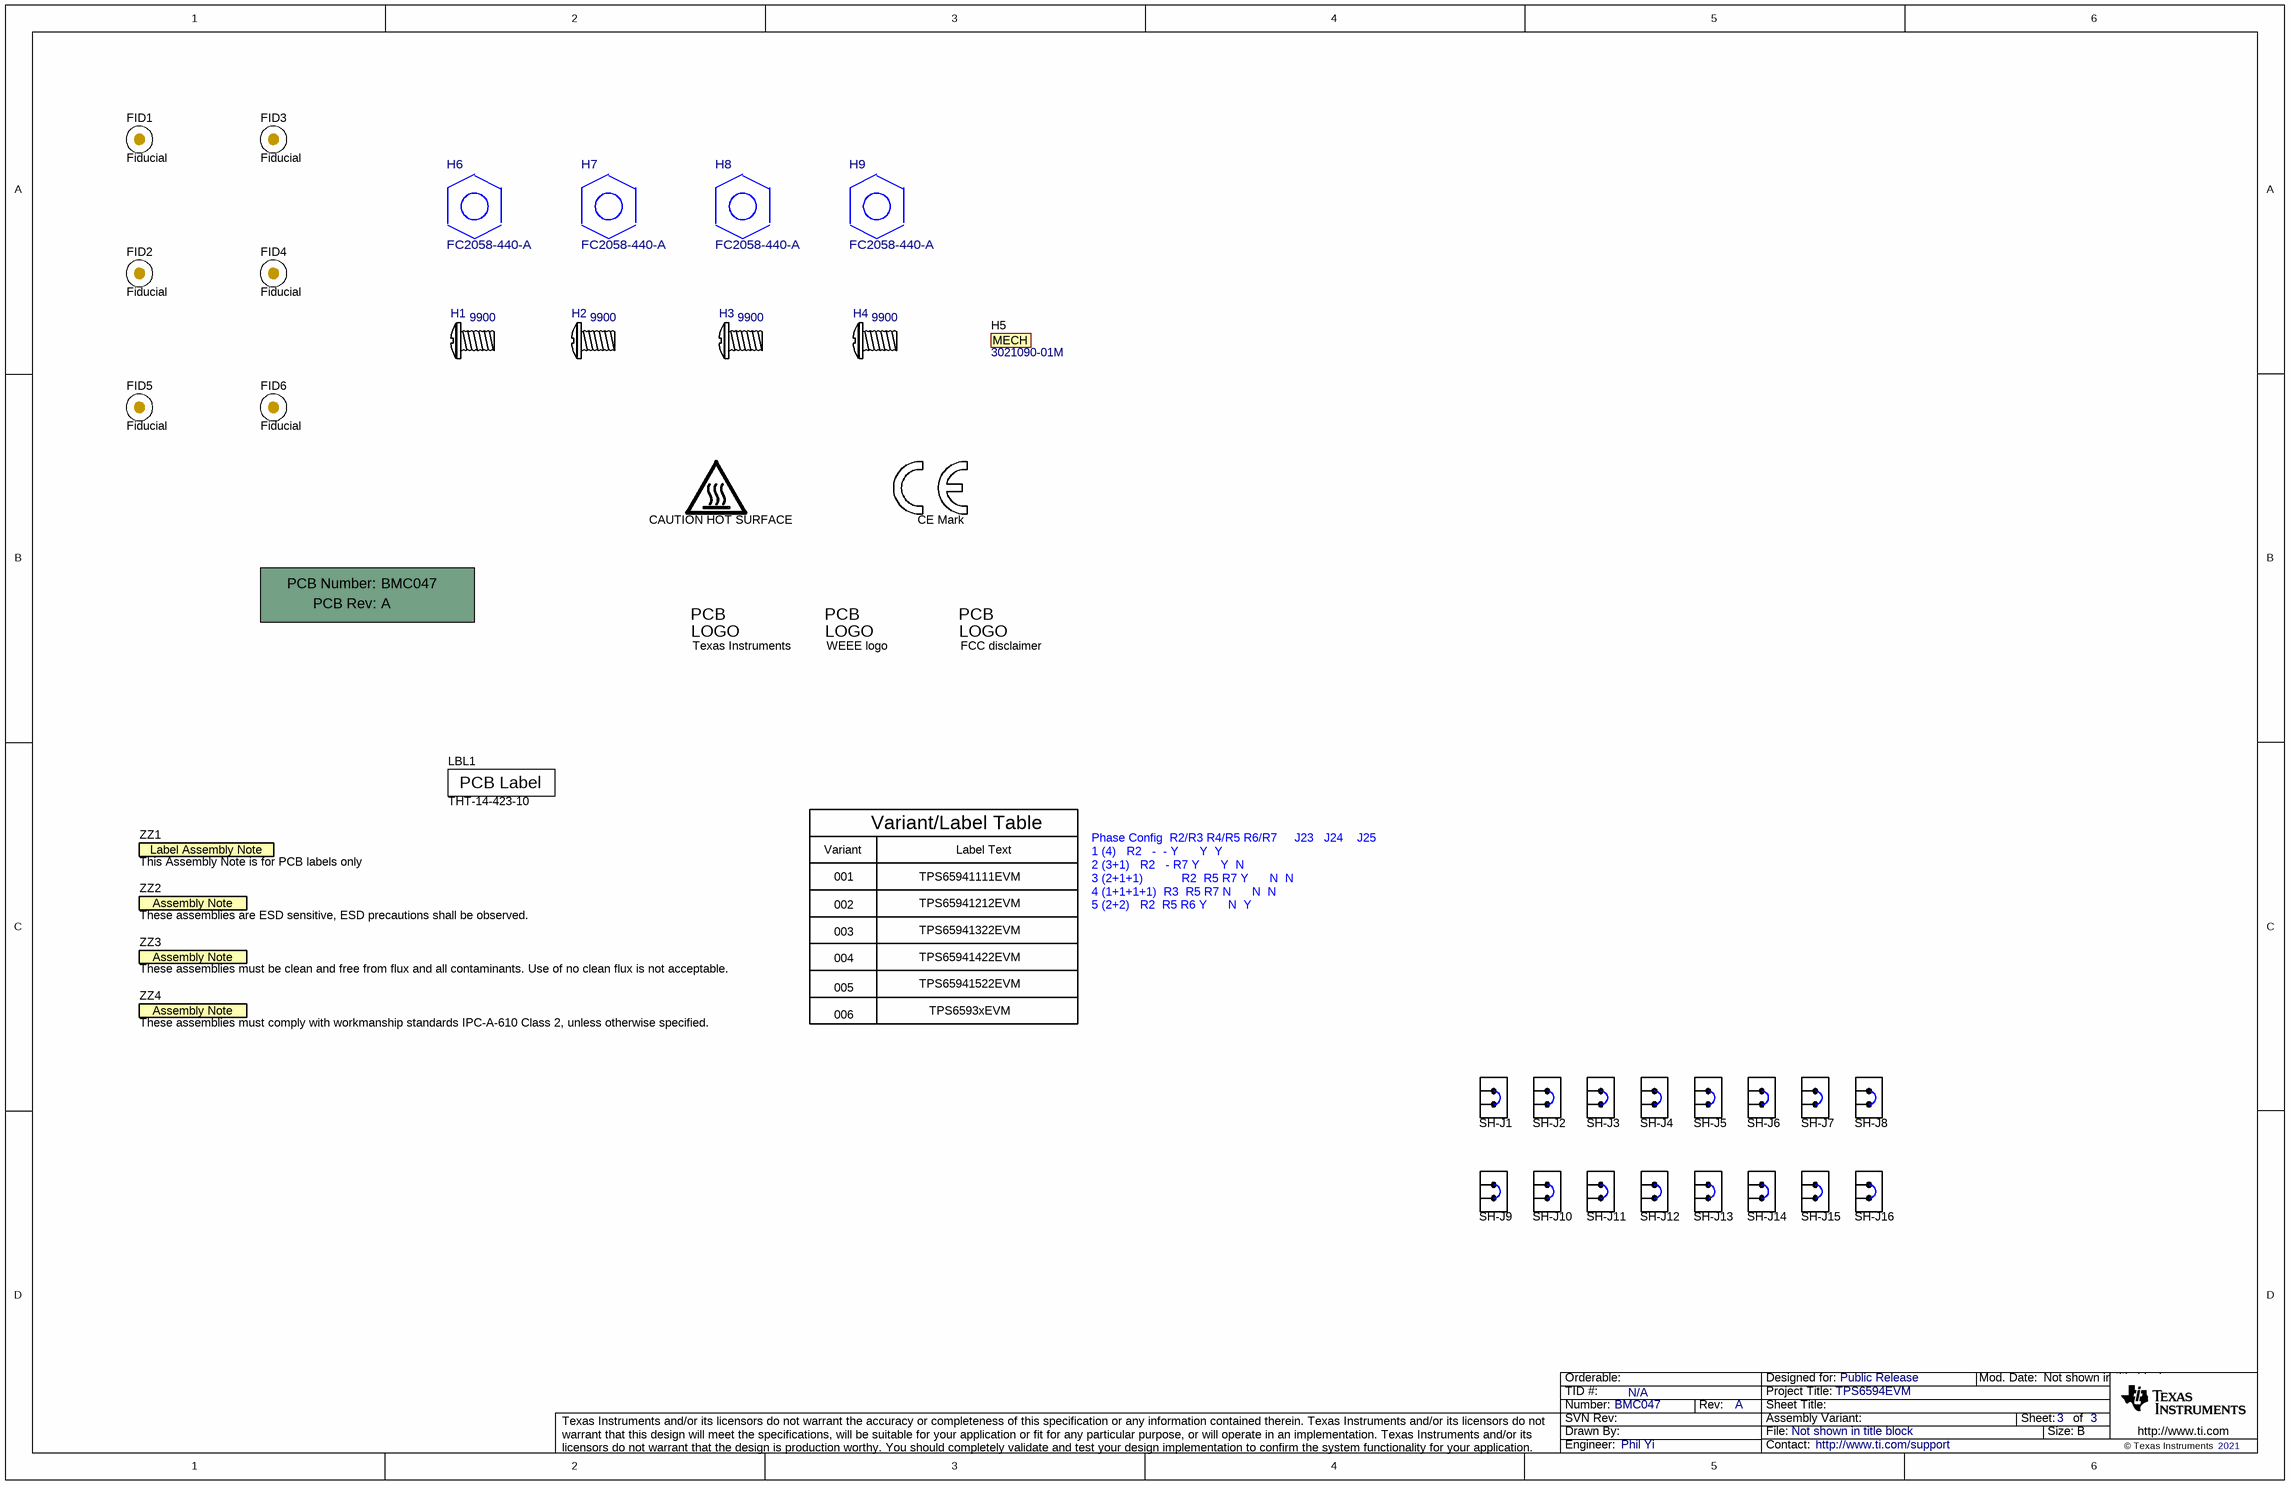
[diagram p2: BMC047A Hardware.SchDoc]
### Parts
!PCB1  Printed Circuit Board  (value not drawn)  (mechanical)
FID1  Fiducial  [Fiducial10-30]  (no BOM)
FID2  Fiducial  [Fiducial10-30]  (no BOM)
FID3  Fiducial  [Fiducial10-30]  (no BOM)
FID4  Fiducial  [Fiducial10-30]  (no BOM)
FID5  Fiducial  [Fiducial10-30]  (no BOM)
FID6  Fiducial  [Fiducial10-30]  (no BOM)
H1  9900  (mechanical)
H2  9900  (mechanical)
H3  9900  (mechanical)
H4  9900  (mechanical)
H5  3021090-01M  (mechanical)
H6  FC2058-440-A  [FP-FC2058-440-A_SPACER-MFG]  (mechanical)
H7  FC2058-440-A  [FP-FC2058-440-A_SPACER-MFG]  (mechanical)
H8  FC2058-440-A  [FP-FC2058-440-A_SPACER-MFG]  (mechanical)
H9  FC2058-440-A  [FP-FC2058-440-A_SPACER-MFG]  (mechanical)
LBL1  THT-14-423-10  [Label_650x200]
LOGO1  CAUTION HOT SURFACE  [IEC_HotSurface_Small]  (no BOM)
Logo2  Texas Instruments  [TI_Stacked_Overlay_Small]  (no BOM)
Logo3  WEEE logo  [WEEE_Minimum]  (no BOM)
Logo4  CE Mark  [CE_Mark_5mm]  (no BOM)
Logo5  FCC disclaimer  [FCC_disclaimer_stacked]  (no BOM)
SH-J1  881545-2  [TE_881545-2]  (value not drawn)
SH-J2  881545-2  [TE_881545-2]  (value not drawn)
SH-J3  881545-2  [TE_881545-2]  (value not drawn)
SH-J4  881545-2  [TE_881545-2]  (value not drawn)
SH-J5  881545-2  [TE_881545-2]  (value not drawn)
SH-J6  881545-2  [TE_881545-2]  (value not drawn)
SH-J7  881545-2  [TE_881545-2]  (value not drawn)
SH-J8  881545-2  [TE_881545-2]  (value not drawn)
SH-J9  881545-2  [TE_881545-2]  (value not drawn)
SH-J10  881545-2  [TE_881545-2]  (value not drawn)
SH-J11  881545-2  [TE_881545-2]  (value not drawn)
SH-J12  881545-2  [TE_881545-2]  (value not drawn)
SH-J13  881545-2  [TE_881545-2]  (value not drawn)
SH-J14  881545-2  [TE_881545-2]  (value not drawn)
SH-J15  881545-2  [TE_881545-2]  (value not drawn)
SH-J16  881545-2  [TE_881545-2]  (value not drawn)
ZZ1  This Assembly Note is for PCB labels only  [AssemblyNoteLabel]  (no BOM)
ZZ2  These assemblies are ESD sensitive, ESD precautions shall be observed.  [AssemblyNote]  (no BOM)
ZZ3  These assemblies must be clean and free from flux and all contaminants. Use of no clean flux is not acceptable.  [AssemblyNote]  (no BOM)
ZZ4  These assemblies must comply with workmanship standards IPC-A-610 Class 2, unless otherwise specified.  [AssemblyNote]  (no BOM)

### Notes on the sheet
- Variant/Label Table
- Variant
- 001
- 002
- TPS65941111EVM
- TPS65941212EVM
- Label Text
- 003
- 004
- TPS65941322EVM
- TPS65941422EVM
- Phase Config	 R2/R3	R4/R5	R6/R7     J23   J24    J25
  1 (4)		 R2	  -	 -	Y      Y	 Y
  2 (3+1)		 R2	  -	R7	Y      Y	 N
  3 (2+1+1)	        	 R2	 R5	R7	Y      N	 N
  4 (1+1+1+1)	 R3	 R5	R7	N      N	 N
  5 (2+2)		 R2	 R5	R6	Y      N	 Y
- 005
- 006
- TPS65941522EVM
- TPS6593xEVM

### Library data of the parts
!PCB1 = CMP-0003618-2: Manufacturer: Any; PartNumber: BMC047
FID1-FID6 = CMP-0077181-1: Fiducial mark.  There is nothing to buy or mount.
H1-H4 = CMP-0003916-1: MACHINE SCREW PAN PHILLIPS 4-40; Manufacturer: Keystone; CompType: Hardware
H5 = CMP-0080604-2: USB A MALE TO USB C Male; Manufacturer: Qualtek; CompType: Mechanical
H6-H9 = CMP-0088082-1: Manufacturer: Fascomp; Symbol Name: SYM-FC2058-440-A
LBL1 = CMP-0003625-1: Manufacturer: Brady
LOGO1 = CMP-0074837-1: IEC 61010-1 Hot Surface Warning; Library Reference: IEC_HotSurface; SymbolCreator: a0412235
Logo2 = CMP-0074838-1: Texas Instrument Corporate Signature; Library Reference: Logo; SymbolCreator: a0412235; Lib Reference: TI_Logo
Logo3 = CMP-0074769-1
Logo4 = CMP-0074844-1: SymbolCreator: a0412235
Logo5 = CMP-0074847-1: FCC_disclaimer; Library Reference: Logo
SH-J1-SH-J16 = CMP-0003677-2: Shunt, 100mil, Gold plated, Black; Manufacturer: TE Connectivity
ZZ1 = CMP-0003616-3
ZZ2 = CMP-0077236-1
ZZ3 = CMP-0077237-1
ZZ4 = CMP-0077238-1

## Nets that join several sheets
+VBUS: BMC047A Main (6 pins), BMC047A USB (11 pins)
GND: BMC047A Main (146 pins), BMC047A USB (70 pins)
MCUVCC: BMC047A Main (5 pins), BMC047A USB (51 pins)
VCCA: BMC047A Main (25 pins), BMC047A USB (9 pins)
VIO_IN: BMC047A Main (11 pins), BMC047A USB (13 pins)
GPIO1: BMC047A Main (J9.1 J11.1 J15.11 U1.32), BMC047A USB (U8.7)
GPIO2: BMC047A Main (J7.4 J9.2 J11.2 U1.33), BMC047A USB (U8.8)
GPIO3: BMC047A Main (J7.7 J9.3 J11.3 U1.46), BMC047A USB (U8.9)
GPIO4: BMC047A Main (J9.4 J11.4 U1.47), BMC047A USB (U8.10)
GPIO5: BMC047A Main (J9.5 J11.5), BMC047A USB (U9.3 U10.3)
GPIO6: BMC047A Main (J9.6 J11.6), BMC047A USB (U9.4 U10.9)
GPIO7: BMC047A Main (J7.9 J9.7 J11.7 U1.18), BMC047A USB (U9.5)
GPIO8: BMC047A Main (J9.8 J11.8 R51.1), BMC047A USB (U9.6)
GPIO9: BMC047A Main (J9.9 J11.9 R54.1), BMC047A USB (U9.7)
GPIO10: BMC047A Main (J9.10 J11.10 R32.1), BMC047A USB (U9.8)
GPIO11: BMC047A Main (J7.11 J9.11 J11.11 U1.53), BMC047A USB (U9.9)
nERR_MCU: BMC047A Main (J7.8), BMC047A USB (U3.62)
nERR_SoC: BMC047A Main (J7.6), BMC047A USB (U3.50)
nINT: BMC047A Main (J15.2 R83.1 U1.14), BMC047A USB (U9.10)
nPWRON: BMC047A Main (5 pins), BMC047A USB (U2.8 U2.11)
nPWRON_S: BMC047A Main (J37.2), BMC047A USB (J29.3 R34.2 U10.4 U10.8)
SCL_I2C1/SCK_SPI: BMC047A Main (U1.31), BMC047A USB (J29.6 R61.2 U8.4)
SCL_I2C2/CS_SPI: BMC047A Main (J15.10), BMC047A USB (J29.7 R63.2 U8.6)
SCLK_SPMI: BMC047A Main (U1.23), BMC047A USB (J29.1 R68.2 U10.5)
SDA_I2C1/SDI_SPI: BMC047A Main (U1.30), BMC047A USB (J29.4 R62.2 U8.3)
SDA_I2C2/SDO_SPI: BMC047A Main (J7.5), BMC047A USB (J29.5 R64.2 U8.5)
SDATA_SPMI: BMC047A Main (U1.24), BMC047A USB (J29.2 R69.2 U10.7)
SPI_EN: BMC047A Main (J7.2), BMC047A USB (R46.2 U3.123 U11.13 U12.15)
TRIG_WDG: BMC047A Main (J7.3 J7.10), BMC047A USB (U3.63)

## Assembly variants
001: not fitted C1 C3 C16 C17 C79 C94 FID1 FID2 FID3 FID4 FID5 FID6 J16 J17 J31 J32 J33 J34 J35 J36 J39 J40 J41 J42 J43 J44 R3 R4 R5 R6 R7 R25 TP9 TP10 TP11 TP12 TP13
002: not fitted C1 C3 C16 C17 C79 C94 FID1 FID2 FID3 FID4 FID5 FID6 J16 J17 J25 J31 J32 J33 J34 J35 J36 J39 J40 J41 J42 J43 J44 R3 R4 R5 R6 R25 TP9 TP10 TP11 TP12 TP13
003: not fitted C1 C3 C16 C17 C79 C94 FID1 FID2 FID3 FID4 FID5 FID6 J16 J17 J24 J25 J31 J32 J33 J34 J35 J36 J39 J40 J41 J42 J43 J44 R3 R4 R6 R25 TP9 TP10 TP11 TP12 TP13
004: not fitted C1 C3 C16 C17 C79 C94 FID1 FID2 FID3 FID4 FID5 FID6 J16 J17 J23 J24 J25 J31 J32 J33 J34 J35 J36 J39 J40 J41 J42 J43 J44 R2 R4 R6 R25 TP9 TP10 TP11 TP12 TP13
005: not fitted C1 C3 C16 C17 C79 C94 FID1 FID2 FID3 FID4 FID5 FID6 J16 J17 J24 J31 J32 J33 J34 J35 J36 J39 J40 J41 J42 J43 J44 R3 R4 R7 R25 TP9 TP10 TP11 TP12 TP13
006: not fitted C1 C3 C16 C17 C79 C94 D1 D3 FID1 FID2 FID3 FID4 FID5 FID6 J16 J17 J23 J24 J25 J31 J32 J33 J34 J35 J36 J39 J40 J41 J42 J43 J44 Q1 R2 R4 R6 R20 R21 R22 R26 R35 TP9 TP10 TP11 TP12 TP13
